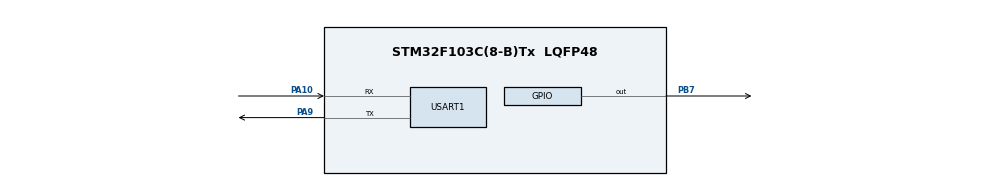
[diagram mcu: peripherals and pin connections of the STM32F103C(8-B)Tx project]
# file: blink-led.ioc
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Mcu.Family=STM32F1
Mcu.Name=STM32F103C(8-B)Tx
Mcu.Package=LQFP48
NVIC.PriorityGroup=NVIC_PRIORITYGROUP_4
PA10.Mode=Asynchronous
PA10.Signal=USART1_RX
PA9.Mode=Asynchronous
PA9.Signal=USART1_TX
PB7.GPIO_PuPd=GPIO_PULLDOWN
PB7.Signal=GPIO_Output
PD0-OSC_IN.Mode=HSE-External-Oscillator
PD0-OSC_IN.Signal=RCC_OSC_IN
PD1-OSC_OUT.Mode=HSE-External-Oscillator
PD1-OSC_OUT.Signal=RCC_OSC_OUT
ProjectManager.HeapSize=0x200
ProjectManager.StackSize=0x400
ProjectManager.TargetToolchain=EWARM V8.32
RCC.AHBFreq_Value=72000000
RCC.APB1CLKDivider=RCC_HCLK_DIV2
RCC.APB1Freq_Value=36000000
RCC.APB1TimFreq_Value=72000000
RCC.APB2Freq_Value=72000000
RCC.APB2TimFreq_Value=72000000
RCC.HCLKFreq_Value=72000000
RCC.PLLMUL=RCC_PLL_MUL9
RCC.PLLSourceVirtual=RCC_PLLSOURCE_HSE
RCC.SYSCLKFreq_VALUE=72000000
RCC.SYSCLKSource=RCC_SYSCLKSOURCE_PLLCLK
RCC.USBFreq_Value=72000000
USART1.VirtualMode=VM_ASYNC
VP_SYS_VS_ND.Mode=No_Debug
board=custom

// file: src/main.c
/* USER CODE BEGIN Header */
/**
  ******************************************************************************
  * @file           : main.c
  * @brief          : Main program body
  ******************************************************************************
  * @attention
  *
  * Copyright (c) 2024 STMicroelectronics.
  * All rights reserved.
  *
  * This software is licensed under terms that can be found in the LICENSE file
  * in the root directory of this software component.
  * If no LICENSE file comes with this software, it is provided AS-IS.
  *
  ******************************************************************************
  */
/* USER CODE END Header */
#include "main.h"

UART_HandleTypeDef huart1;

void SystemClock_Config(void);
static void MX_GPIO_Init(void);
static void MX_USART1_UART_Init(void);

int main(void)
{

  /* MCU Configuration--------------------------------------------------------*/

  /* Reset of all peripherals, Initializes the Flash interface and the Systick. */
  HAL_Init();

  /* Configure the system clock */
  SystemClock_Config();

  /* Initialize all configured peripherals */
  MX_GPIO_Init();
  MX_USART1_UART_Init();

  /* Infinite loop */
  /* USER CODE BEGIN WHILE */
  while (1)
  {
    HAL_GPIO_TogglePin(GPIOB, GPIO_PIN_7);
    HAL_Delay(250);
    HAL_UART_Transmit(&huart1, (uint8_t *)"Hello dev.to", 13, 1000);
    /* USER CODE END WHILE */
  }
}

void SystemClock_Config(void)
{
  RCC_OscInitTypeDef RCC_OscInitStruct = {0};
  RCC_ClkInitTypeDef RCC_ClkInitStruct = {0};

  /** Initializes the RCC Oscillators according to the specified parameters
  * in the RCC_OscInitTypeDef structure.
  */
  RCC_OscInitStruct.OscillatorType = RCC_OSCILLATORTYPE_HSI;
  RCC_OscInitStruct.HSIState = RCC_HSI_ON;
  RCC_OscInitStruct.HSICalibrationValue = RCC_HSICALIBRATION_DEFAULT;
  RCC_OscInitStruct.PLL.PLLState = RCC_PLL_ON;
  RCC_OscInitStruct.PLL.PLLSource = RCC_PLLSOURCE_HSI_DIV2;
  RCC_OscInitStruct.PLL.PLLMUL = RCC_PLL_MUL16;
  if (HAL_RCC_OscConfig(&RCC_OscInitStruct) != HAL_OK)
  {
    Error_Handler();
  }

  /** Initializes the CPU, AHB and APB buses clocks
  */
  RCC_ClkInitStruct.ClockType = RCC_CLOCKTYPE_HCLK|RCC_CLOCKTYPE_SYSCLK
                              |RCC_CLOCKTYPE_PCLK1|RCC_CLOCKTYPE_PCLK2;
  RCC_ClkInitStruct.SYSCLKSource = RCC_SYSCLKSOURCE_PLLCLK;
  RCC_ClkInitStruct.AHBCLKDivider = RCC_SYSCLK_DIV1;
  RCC_ClkInitStruct.APB1CLKDivider = RCC_HCLK_DIV2;
  RCC_ClkInitStruct.APB2CLKDivider = RCC_HCLK_DIV1;

  if (HAL_RCC_ClockConfig(&RCC_ClkInitStruct, FLASH_LATENCY_2) != HAL_OK)
  {
    Error_Handler();
  }
}

static void MX_USART1_UART_Init(void)
{

  huart1.Instance = USART1;
  huart1.Init.BaudRate = 115200;
  huart1.Init.WordLength = UART_WORDLENGTH_8B;
  huart1.Init.StopBits = UART_STOPBITS_1;
  huart1.Init.Parity = UART_PARITY_NONE;
  huart1.Init.Mode = UART_MODE_TX_RX;
  huart1.Init.HwFlowCtl = UART_HWCONTROL_NONE;
  huart1.Init.OverSampling = UART_OVERSAMPLING_16;
  if (HAL_UART_Init(&huart1) != HAL_OK)
  {
    Error_Handler();
  }

}

static void MX_GPIO_Init(void)
{
  GPIO_InitTypeDef GPIO_InitStruct = {0};

  /* GPIO Ports Clock Enable */
  __HAL_RCC_GPIOD_CLK_ENABLE();
  __HAL_RCC_GPIOA_CLK_ENABLE();
  __HAL_RCC_GPIOB_CLK_ENABLE();

  /*Configure GPIO pin Output Level */
  HAL_GPIO_WritePin(GPIOB, GPIO_PIN_7, GPIO_PIN_RESET);

  /*Configure GPIO pin : PB7 */
  GPIO_InitStruct.Pin = GPIO_PIN_7;
  GPIO_InitStruct.Mode = GPIO_MODE_OUTPUT_PP;
  GPIO_InitStruct.Pull = GPIO_PULLDOWN;
  GPIO_InitStruct.Speed = GPIO_SPEED_FREQ_LOW;
  HAL_GPIO_Init(GPIOB, &GPIO_InitStruct);

}

void Error_Handler(void)
{
  __disable_irq();
  while (1)
  {
  }
}
